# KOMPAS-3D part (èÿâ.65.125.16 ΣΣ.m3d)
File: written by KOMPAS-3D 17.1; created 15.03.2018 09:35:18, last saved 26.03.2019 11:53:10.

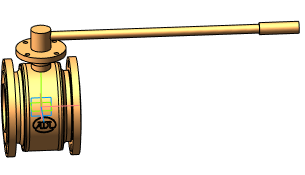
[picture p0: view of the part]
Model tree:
1. Операция без истории:3  (labels: Сталь 20  ГОСТ 1050-2013)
